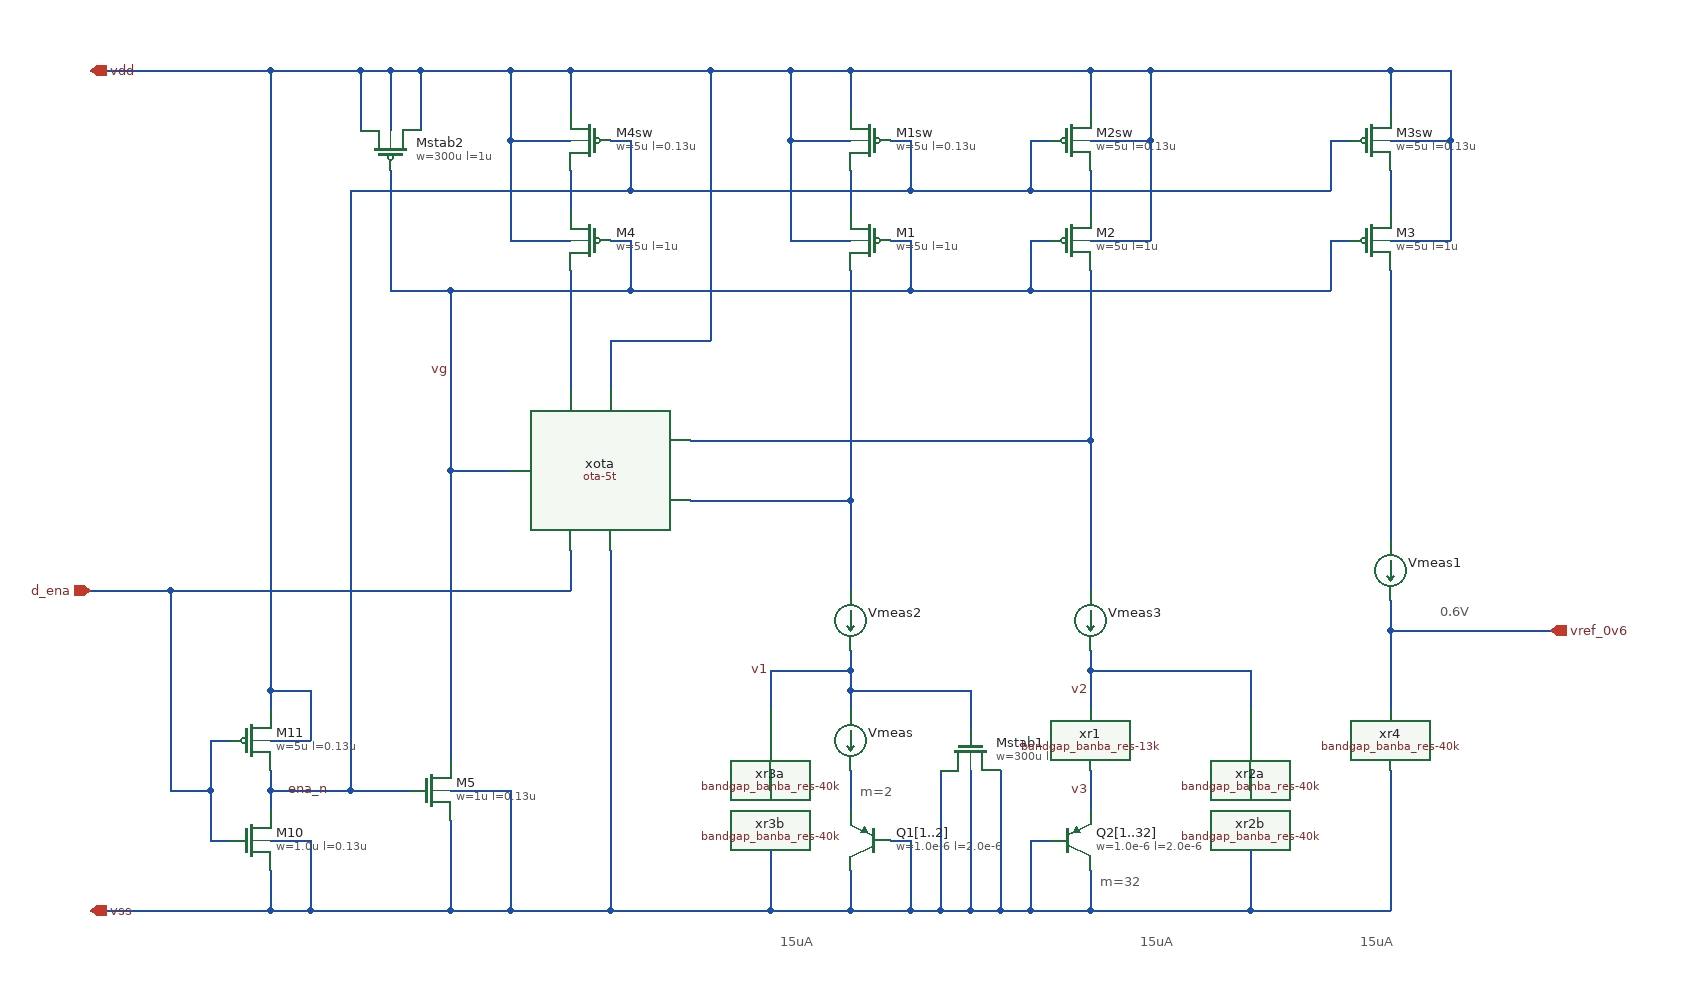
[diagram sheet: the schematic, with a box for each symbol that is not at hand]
v {xschem version=3.4.6 file_version=1.2}
G {}
K {}
V {}
S {}
E {}
T {m=32} 1140 -240 0 0 0.4 0.4 {}
T {15uA} 820 -180 0 0 0.4 0.4 {}
T {15uA} 1180 -180 0 0 0.4 0.4 {}
T {15uA} 1400 -180 0 0 0.4 0.4 {}
T {m=2} 900 -330 0 0 0.4 0.4 {}
T {0.6V} 1480 -510 0 0 0.4 0.4 {}
N 1130 -240 1130 -200 {lab=vss}
N 890 -240 890 -200 {lab=vss}
N 1070 -270 1090 -270 {lab=vss}
N 1070 -270 1070 -200 {lab=vss}
N 930 -270 950 -270 {lab=vss}
N 950 -270 950 -200 {lab=vss}
N 890 -200 950 -200 {
lab=vss}
N 1130 -340 1130 -300 {lab=v3}
N 830 -870 890 -870 {lab=vdd}
N 1130 -870 1190 -870 {lab=vdd}
N 890 -340 890 -300 {lab=#net1}
N 1070 -200 1130 -200 {lab=vss}
N 550 -870 610 -870 {lab=vdd}
N 490 -640 550 -640 {lab=vg}
N 1430 -870 1490 -870 {lab=vdd}
N 1370 -870 1390 -870 {lab=vg}
N 1370 -870 1370 -820 {lab=vg}
N 810 -440 810 -400 {lab=v1}
N 810 -440 890 -440 {lab=v1}
N 810 -200 890 -200 {
lab=vss}
N 1130 -440 1290 -440 {lab=v2}
N 1290 -440 1290 -400 {lab=v2}
N 1290 -200 1430 -200 {lab=vss}
N 650 -560 650 -200 {lab=vss}
N 650 -770 750 -770 {lab=vdd}
N 650 -770 650 -720 {lab=vdd}
N 1430 -840 1430 -570 {lab=#net2}
N 890 -460 890 -440 {lab=v1}
N 1130 -440 1130 -400 {lab=v2}
N 1130 -460 1130 -440 {lab=v2}
N 1430 -340 1430 -200 {lab=vss}
N 610 -840 610 -720 {lab=#net3}
N 730 -610 890 -610 {lab=#net4}
N 890 -840 890 -610 {lab=#net4}
N 730 -670 1130 -670 {lab=#net5}
N 1130 -840 1130 -670 {lab=#net5}
N 1430 -480 1430 -400 {lab=vref_0v6}
N 890 -420 890 -400 {lab=v1}
N 490 -290 490 -200 {lab=vss}
N 490 -640 490 -350 {lab=vg}
N 490 -200 550 -200 {
lab=vss}
N 1490 -970 1490 -870 {lab=vdd}
N 1430 -1040 1490 -1040 {lab=vdd}
N 1190 -970 1190 -870 {lab=vdd}
N 1130 -1040 1190 -1040 {lab=vdd}
N 750 -1040 830 -1040 {lab=vdd}
N 610 -1040 750 -1040 {lab=vdd}
N 750 -1040 750 -770 {lab=vdd}
N 550 -970 550 -870 {lab=vdd}
N 250 -270 270 -270 {lab=d_ena}
N 250 -320 250 -270 {lab=d_ena}
N 250 -370 270 -370 {lab=d_ena}
N 310 -240 310 -200 {lab=vss}
N 310 -420 310 -400 {lab=vdd}
N 310 -1040 310 -420 {lab=vdd}
N 350 -420 350 -370 {lab=vdd}
N 210 -320 250 -320 {lab=d_ena}
N 250 -370 250 -320 {lab=d_ena}
N 210 -520 210 -320 {lab=d_ena}
N 130 -520 210 -520 {lab=d_ena}
N 310 -320 310 -300 {lab=ena_n}
N 310 -420 350 -420 {lab=vdd}
N 310 -370 350 -370 {lab=vdd}
N 1040 -200 1070 -200 {
lab=vss}
N 890 -440 890 -420 {lab=v1}
N 310 -340 310 -320 {lab=ena_n}
N 890 -610 890 -520 {lab=#net4}
N 1130 -670 1130 -520 {lab=#net5}
N 550 -200 650 -200 {
lab=vss}
N 610 -560 610 -520 {lab=d_ena}
N 490 -320 550 -320 {lab=vss}
N 550 -320 550 -200 {lab=vss}
N 390 -320 450 -320 {lab=ena_n}
N 460 -1040 550 -1040 {lab=vdd}
N 490 -820 670 -820 {lab=vg}
N 490 -820 490 -640 {lab=vg}
N 400 -1040 400 -980 {lab=vdd}
N 310 -1040 400 -1040 {lab=vdd}
N 430 -1040 430 -980 {lab=vdd}
N 400 -1040 430 -1040 {lab=vdd}
N 460 -1040 460 -980 {lab=vdd}
N 430 -1040 460 -1040 {lab=vdd}
N 890 -420 1010 -420 {lab=v1}
N 1010 -420 1010 -380 {lab=v1}
N 980 -340 980 -200 {lab=vss}
N 950 -200 980 -200 {
lab=vss}
N 1010 -340 1010 -200 {lab=vss}
N 980 -200 1010 -200 {
lab=vss}
N 1040 -340 1040 -200 {lab=vss}
N 1010 -200 1040 -200 {
lab=vss}
N 1290 -260 1290 -200 {lab=vss}
N 1130 -200 1290 -200 {lab=vss}
N 1290 -340 1290 -320 {lab=#net6}
N 810 -260 810 -200 {lab=vss}
N 650 -200 810 -200 {
lab=vss}
N 810 -340 810 -320 {lab=#net7}
N 1430 -1040 1430 -1000 {lab=vdd}
N 1190 -1040 1430 -1040 {lab=vdd}
N 1430 -940 1430 -900 {lab=#net8}
N 1430 -970 1490 -970 {lab=vdd}
N 1490 -1040 1490 -970 {lab=vdd}
N 1130 -940 1130 -900 {lab=#net9}
N 1130 -970 1190 -970 {lab=vdd}
N 1190 -1040 1190 -970 {lab=vdd}
N 1130 -1040 1130 -1000 {lab=vdd}
N 890 -1040 1130 -1040 {lab=vdd}
N 890 -1040 890 -1000 {lab=vdd}
N 830 -1040 890 -1040 {lab=vdd}
N 830 -970 890 -970 {lab=vdd}
N 830 -970 830 -870 {lab=vdd}
N 890 -940 890 -900 {lab=#net10}
N 610 -940 610 -900 {lab=#net11}
N 610 -1040 610 -1000 {lab=vdd}
N 550 -1040 610 -1040 {lab=vdd}
N 550 -970 610 -970 {lab=vdd}
N 550 -1040 550 -970 {lab=vdd}
N 830 -1040 830 -970 {lab=vdd}
N 1370 -970 1390 -970 {lab=ena_n}
N 1370 -970 1370 -920 {lab=ena_n}
N 1070 -920 1370 -920 {lab=ena_n}
N 210 -520 610 -520 {lab=d_ena}
N 390 -920 390 -320 {lab=ena_n}
N 310 -320 390 -320 {lab=ena_n}
N 650 -970 670 -970 {lab=ena_n}
N 670 -970 670 -920 {lab=ena_n}
N 390 -920 670 -920 {lab=ena_n}
N 930 -970 950 -970 {lab=ena_n}
N 950 -970 950 -920 {lab=ena_n}
N 670 -920 950 -920 {lab=ena_n}
N 1070 -970 1090 -970 {lab=ena_n}
N 1070 -970 1070 -920 {lab=ena_n}
N 950 -920 1070 -920 {lab=ena_n}
N 650 -870 670 -870 {lab=vg}
N 930 -870 950 -870 {lab=vg}
N 670 -820 950 -820 {lab=vg}
N 1070 -870 1090 -870 {lab=vg}
N 1070 -870 1070 -820 {lab=vg}
N 1070 -820 1370 -820 {lab=vg}
N 670 -870 670 -820 {lab=vg}
N 950 -870 950 -820 {lab=vg}
N 430 -940 430 -820 {lab=vg}
N 430 -820 490 -820 {lab=vg}
N 950 -820 1070 -820 {lab=vg}
N 130 -1040 310 -1040 {lab=vdd}
N 350 -200 490 -200 {lab=vss}
N 130 -200 310 -200 {lab=vss}
N 1430 -480 1590 -480 {lab=vref_0v6}
N 1430 -510 1430 -480 {lab=vref_0v6}
N 310 -270 350 -270 {lab=vss}
N 350 -270 350 -200 {lab=vss}
N 310 -200 350 -200 {lab=vss}
C {devices/title.sym} 160 -30 0 0 {name=l5 author="(c) 2025 H. Pretl, Apache-2.0 license"}
C {sg13g2_pr/pnpMPA.sym} 910 -270 0 1 {name=Q1[1..2]
model=pnpMPA
spiceprefix=X
w=1.0e-6
l=2.0e-6
m=1
}
C {sg13g2_pr/pnpMPA.sym} 1110 -270 0 0 {name=Q2[1..32]
model=pnpMPA
spiceprefix=X
w=1.0e-6
l=2.0e-6
m=1
}
C {devices/ammeter.sym} 890 -370 0 0 {name=Vmeas savecurrent=true spice_ignore=0}
C {devices/ammeter.sym} 1430 -540 0 0 {name=Vmeas1 savecurrent=true spice_ignore=0}
C {devices/lab_pin.sym} 1130 -420 0 0 {name=p3 sig_type=std_logic lab=v2}
C {devices/lab_pin.sym} 1130 -320 0 0 {name=p4 sig_type=std_logic lab=v3}
C {ota-5t.sym} 650 -640 0 1 {name=xota}
C {sg13g2_pr/sg13_lv_pmos.sym} 630 -870 0 1 {name=M4
l=1u
w=5u
ng=1
m=1
model=sg13_lv_pmos
spiceprefix=X
}
C {devices/ammeter.sym} 890 -490 0 0 {name=Vmeas2 savecurrent=true spice_ignore=0}
C {devices/ammeter.sym} 1130 -490 0 0 {name=Vmeas3 savecurrent=true spice_ignore=0}
C {devices/lab_pin.sym} 810 -440 0 0 {name=p5 sig_type=std_logic lab=v1}
C {sg13g2_pr/sg13_lv_pmos.sym} 910 -870 0 1 {name=M1
l=1u
w=5u
ng=1
m=1
model=sg13_lv_pmos
spiceprefix=X
}
C {sg13g2_pr/sg13_lv_pmos.sym} 1110 -870 0 0 {name=M2
l=1u
w=5u
ng=1
m=1
model=sg13_lv_pmos
spiceprefix=X
}
C {sg13g2_pr/sg13_lv_pmos.sym} 1410 -870 0 0 {name=M3
l=1u
w=5u
ng=1
m=1
model=sg13_lv_pmos
spiceprefix=X
}
C {devices/lab_pin.sym} 490 -740 0 0 {name=p6 sig_type=std_logic lab=vg}
C {sg13g2_pr/sg13_lv_nmos.sym} 470 -320 0 0 {name=M5
l=0.13u
w=1u
ng=1
m=1
model=sg13_lv_nmos
spiceprefix=X
}
C {sg13g2_pr/sg13_lv_nmos.sym} 290 -270 0 0 {name=M10
l=0.13u
w=1.0u
ng=1
m=1
model=sg13_lv_nmos
spiceprefix=X
}
C {sg13g2_pr/sg13_lv_pmos.sym} 290 -370 0 0 {name=M11
l=0.13u
w=5u
ng=1
m=1
model=sg13_lv_pmos
spiceprefix=X
}
C {sg13g2_pr/sg13_lv_pmos.sym} 430 -960 1 1 {name=Mstab2
l=1u
w=300u
ng=60
m=1
model=sg13_lv_pmos
spiceprefix=X
}
C {sg13g2_pr/sg13_lv_nmos.sym} 1010 -360 3 1 {name=Mstab1
l=1u
w=300u
ng=60
m=1
model=sg13_lv_nmos
spiceprefix=X
}
C {devices/lab_wire.sym} 370 -320 0 0 {name=p8 sig_type=std_logic lab=ena_n}
C {bandgap_banba_res-13k.sym} 1130 -340 0 0 {name=xr1}
C {bandgap_banba_res-40k.sym} 1290 -340 0 0 {name=xr2a}
C {bandgap_banba_res-40k.sym} 1290 -260 0 0 {name=xr2b}
C {bandgap_banba_res-40k.sym} 810 -340 0 1 {name=xr3a}
C {bandgap_banba_res-40k.sym} 810 -260 0 1 {name=xr3b}
C {bandgap_banba_res-40k.sym} 1430 -340 0 0 {name=xr4}
C {sg13g2_pr/sg13_lv_pmos.sym} 1410 -970 0 0 {name=M3sw
l=0.13u
w=5u
ng=1
m=1
model=sg13_lv_pmos
spiceprefix=X
}
C {sg13g2_pr/sg13_lv_pmos.sym} 1110 -970 0 0 {name=M2sw
l=0.13u
w=5u
ng=1
m=1
model=sg13_lv_pmos
spiceprefix=X
}
C {sg13g2_pr/sg13_lv_pmos.sym} 910 -970 0 1 {name=M1sw
l=0.13u
w=5u
ng=1
m=1
model=sg13_lv_pmos
spiceprefix=X
}
C {sg13g2_pr/sg13_lv_pmos.sym} 630 -970 0 1 {name=M4sw
l=0.13u
w=5u
ng=1
m=1
model=sg13_lv_pmos
spiceprefix=X
}
C {devices/iopin.sym} 130 -1040 0 1 {name=p9 lab=vdd}
C {devices/iopin.sym} 130 -200 0 1 {name=p2 lab=vss}
C {devices/ipin.sym} 130 -520 0 0 {name=p7 lab=d_ena}
C {devices/opin.sym} 1590 -480 0 0 {name=p10 lab=vref_0v6}
